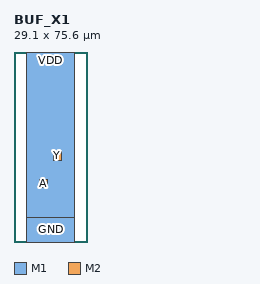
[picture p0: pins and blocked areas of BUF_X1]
MACRO BUF_X1
  CLASS CORE ;
  ORIGIN 0 0 ;
  SIZE 29.100 BY 75.600 ;
  SYMMETRY X Y ;
  SITE TR1um_access_site ;
  PIN VDD
    DIRECTION INOUT ;
    USE POWER ;
    PORT
      LAYER M1 ;
        RECT 5.000 0.000 24.100 75.600 ;
    END
  END VDD
  PIN GND
    DIRECTION INOUT ;
    USE GROUND ;
    PORT
      LAYER M1 ;
        RECT 5.000 0.000 24.100 9.800 ;
    END
  END GND
  PIN A
    DIRECTION INPUT ;
    USE SIGNAL ;
    PORT
      LAYER M2 ;
        RECT 10.100 21.600 13.500 25.000 ;
    END
  END A
  PIN Y
    DIRECTION OUTPUT ;
    USE SIGNAL ;
    PORT
      LAYER M2 ;
        RECT 15.600 32.600 19.000 36.000 ;
    END
  END Y
  OBS
    LAYER M1 ;
      RECT 9.100 6.400 13.650 16.200 ;
    LAYER M1 ;
      RECT 10.100 17.600 13.650 25.000 ;
    LAYER M1 ;
      RECT 15.450 14.400 18.500 29.000 ;
    LAYER M1 ;
      RECT 9.100 27.200 13.650 51.200 ;
    LAYER M1 ;
      RECT 15.600 6.400 21.900 51.200 ;
    LAYER V1 ;
      RECT 11.100 22.600 12.500 24.000 ;
    LAYER V1 ;
      RECT 16.600 33.600 18.000 35.000 ;
  END
END BUF_X1
